VERSION 5.7 ;
  NOWIREEXTENSIONATPIN ON ;
  DIVIDERCHAR "/" ;
  BUSBITCHARS "[]" ;
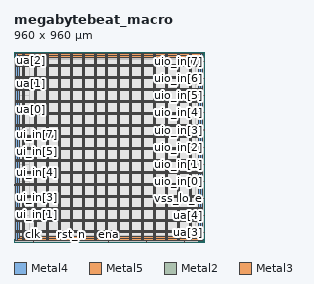
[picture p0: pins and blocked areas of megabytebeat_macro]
MACRO megabytebeat_macro
  CLASS BLOCK ;
  FOREIGN megabytebeat_macro ;
  ORIGIN 0.000 0.000 ;
  SIZE 960.000 BY 960.000 ;
  PIN VDD_BB
    DIRECTION INOUT ;
    USE POWER ;
    PORT
      LAYER Metal4 ;
        RECT 18.240 19.360 26.240 941.040 ;
    END
    PORT
      LAYER Metal4 ;
        RECT 933.600 19.360 941.600 941.040 ;
    END
    PORT
      LAYER Metal5 ;
        RECT 18.240 19.360 941.600 27.360 ;
    END
    PORT
      LAYER Metal5 ;
        RECT 18.240 933.040 941.600 941.040 ;
    END
    PORT
      LAYER Metal4 ;
        RECT 44.560 9.360 48.560 951.040 ;
    END
    PORT
      LAYER Metal4 ;
        RECT 104.560 9.360 108.560 951.040 ;
    END
    PORT
      LAYER Metal4 ;
        RECT 164.560 9.360 168.560 951.040 ;
    END
    PORT
      LAYER Metal4 ;
        RECT 224.560 9.360 228.560 951.040 ;
    END
    PORT
      LAYER Metal4 ;
        RECT 284.560 9.360 288.560 951.040 ;
    END
    PORT
      LAYER Metal4 ;
        RECT 344.560 9.360 348.560 951.040 ;
    END
    PORT
      LAYER Metal4 ;
        RECT 404.560 9.360 408.560 951.040 ;
    END
    PORT
      LAYER Metal4 ;
        RECT 464.560 9.360 468.560 951.040 ;
    END
    PORT
      LAYER Metal4 ;
        RECT 524.560 9.360 528.560 951.040 ;
    END
    PORT
      LAYER Metal4 ;
        RECT 584.560 9.360 588.560 951.040 ;
    END
    PORT
      LAYER Metal4 ;
        RECT 644.560 9.360 648.560 951.040 ;
    END
    PORT
      LAYER Metal4 ;
        RECT 704.560 9.360 708.560 951.040 ;
    END
    PORT
      LAYER Metal4 ;
        RECT 764.560 9.360 768.560 951.040 ;
    END
    PORT
      LAYER Metal4 ;
        RECT 824.560 9.360 828.560 951.040 ;
    END
    PORT
      LAYER Metal4 ;
        RECT 884.560 9.360 888.560 951.040 ;
    END
    PORT
      LAYER Metal5 ;
        RECT 8.240 46.010 951.600 50.010 ;
    END
    PORT
      LAYER Metal5 ;
        RECT 8.240 106.010 951.600 110.010 ;
    END
    PORT
      LAYER Metal5 ;
        RECT 8.240 166.010 951.600 170.010 ;
    END
    PORT
      LAYER Metal5 ;
        RECT 8.240 226.010 951.600 230.010 ;
    END
    PORT
      LAYER Metal5 ;
        RECT 8.240 286.010 951.600 290.010 ;
    END
    PORT
      LAYER Metal5 ;
        RECT 8.240 346.010 951.600 350.010 ;
    END
    PORT
      LAYER Metal5 ;
        RECT 8.240 406.010 951.600 410.010 ;
    END
    PORT
      LAYER Metal5 ;
        RECT 8.240 466.010 951.600 470.010 ;
    END
    PORT
      LAYER Metal5 ;
        RECT 8.240 526.010 951.600 530.010 ;
    END
    PORT
      LAYER Metal5 ;
        RECT 8.240 586.010 951.600 590.010 ;
    END
    PORT
      LAYER Metal5 ;
        RECT 8.240 646.010 951.600 650.010 ;
    END
    PORT
      LAYER Metal5 ;
        RECT 8.240 706.010 951.600 710.010 ;
    END
    PORT
      LAYER Metal5 ;
        RECT 8.240 766.010 951.600 770.010 ;
    END
    PORT
      LAYER Metal5 ;
        RECT 8.240 826.010 951.600 830.010 ;
    END
    PORT
      LAYER Metal5 ;
        RECT 8.240 886.010 951.600 890.010 ;
    END
  END VDD_BB
  PIN VSS
    DIRECTION INOUT ;
    USE GROUND ;
    PORT
      LAYER Metal4 ;
        RECT 8.240 9.360 16.240 951.040 ;
    END
    PORT
      LAYER Metal4 ;
        RECT 943.600 9.360 951.600 951.040 ;
    END
    PORT
      LAYER Metal5 ;
        RECT 8.240 9.360 951.600 17.360 ;
    END
    PORT
      LAYER Metal5 ;
        RECT 8.240 943.040 951.600 951.040 ;
    END
    PORT
      LAYER Metal4 ;
        RECT 50.560 9.360 54.560 951.040 ;
    END
    PORT
      LAYER Metal4 ;
        RECT 110.560 9.360 114.560 951.040 ;
    END
    PORT
      LAYER Metal4 ;
        RECT 170.560 9.360 174.560 951.040 ;
    END
    PORT
      LAYER Metal4 ;
        RECT 230.560 9.360 234.560 951.040 ;
    END
    PORT
      LAYER Metal4 ;
        RECT 290.560 9.360 294.560 951.040 ;
    END
    PORT
      LAYER Metal4 ;
        RECT 350.560 9.360 354.560 951.040 ;
    END
    PORT
      LAYER Metal4 ;
        RECT 410.560 9.360 414.560 951.040 ;
    END
    PORT
      LAYER Metal4 ;
        RECT 470.560 9.360 474.560 951.040 ;
    END
    PORT
      LAYER Metal4 ;
        RECT 530.560 9.360 534.560 951.040 ;
    END
    PORT
      LAYER Metal4 ;
        RECT 590.560 9.360 594.560 951.040 ;
    END
    PORT
      LAYER Metal4 ;
        RECT 650.560 9.360 654.560 951.040 ;
    END
    PORT
      LAYER Metal4 ;
        RECT 710.560 9.360 714.560 951.040 ;
    END
    PORT
      LAYER Metal4 ;
        RECT 770.560 9.360 774.560 951.040 ;
    END
    PORT
      LAYER Metal4 ;
        RECT 830.560 9.360 834.560 951.040 ;
    END
    PORT
      LAYER Metal4 ;
        RECT 890.560 9.360 894.560 951.040 ;
    END
    PORT
      LAYER Metal5 ;
        RECT 8.240 52.010 951.600 56.010 ;
    END
    PORT
      LAYER Metal5 ;
        RECT 8.240 112.010 951.600 116.010 ;
    END
    PORT
      LAYER Metal5 ;
        RECT 8.240 172.010 951.600 176.010 ;
    END
    PORT
      LAYER Metal5 ;
        RECT 8.240 232.010 951.600 236.010 ;
    END
    PORT
      LAYER Metal5 ;
        RECT 8.240 292.010 951.600 296.010 ;
    END
    PORT
      LAYER Metal5 ;
        RECT 8.240 352.010 951.600 356.010 ;
    END
    PORT
      LAYER Metal5 ;
        RECT 8.240 412.010 951.600 416.010 ;
    END
    PORT
      LAYER Metal5 ;
        RECT 8.240 472.010 951.600 476.010 ;
    END
    PORT
      LAYER Metal5 ;
        RECT 8.240 532.010 951.600 536.010 ;
    END
    PORT
      LAYER Metal5 ;
        RECT 8.240 592.010 951.600 596.010 ;
    END
    PORT
      LAYER Metal5 ;
        RECT 8.240 652.010 951.600 656.010 ;
    END
    PORT
      LAYER Metal5 ;
        RECT 8.240 712.010 951.600 716.010 ;
    END
    PORT
      LAYER Metal5 ;
        RECT 8.240 772.010 951.600 776.010 ;
    END
    PORT
      LAYER Metal5 ;
        RECT 8.240 832.010 951.600 836.010 ;
    END
    PORT
      LAYER Metal5 ;
        RECT 8.240 892.010 951.600 896.010 ;
    END
  END VSS
  PIN clk
    DIRECTION INPUT ;
    USE SIGNAL ;
    ANTENNAGATEAREA 5.464000 ;
    PORT
      LAYER Metal2 ;
        RECT 96.320 0.000 96.880 0.560 ;
    END
  END clk
  PIN ena
    DIRECTION INPUT ;
    USE SIGNAL ;
    ANTENNAGATEAREA 0.498500 ;
    PORT
      LAYER Metal2 ;
        RECT 479.360 0.000 479.920 0.560 ;
    END
  END ena
  PIN rst_n
    DIRECTION INPUT ;
    USE SIGNAL ;
    ANTENNAGATEAREA 0.498500 ;
    PORT
      LAYER Metal2 ;
        RECT 287.840 0.000 288.400 0.560 ;
    END
  END rst_n
  PIN ua[0]
    DIRECTION INOUT ;
    USE SIGNAL ;
    PORT
      LAYER Metal3 ;
        RECT 0.000 670.880 0.560 671.440 ;
    END
  END ua[0]
  PIN ua[1]
    DIRECTION INOUT ;
    USE SIGNAL ;
    PORT
      LAYER Metal3 ;
        RECT 0.000 798.560 0.560 799.120 ;
    END
  END ua[1]
  PIN ua[2]
    DIRECTION INOUT ;
    USE SIGNAL ;
    PORT
      LAYER Metal3 ;
        RECT 0.000 926.240 0.560 926.800 ;
    END
  END ua[2]
  PIN ua[3]
    DIRECTION INOUT ;
    USE SIGNAL ;
    PORT
      LAYER Metal3 ;
        RECT 959.440 48.160 960.000 48.720 ;
    END
  END ua[3]
  PIN ua[4]
    DIRECTION INOUT ;
    USE SIGNAL ;
    PORT
      LAYER Metal3 ;
        RECT 959.440 134.400 960.000 134.960 ;
    END
  END ua[4]
  PIN ui_in[0]
    DIRECTION INPUT ;
    USE SIGNAL ;
    ANTENNAGATEAREA 0.498500 ;
    PORT
      LAYER Metal3 ;
        RECT 0.000 32.480 0.560 33.040 ;
    END
  END ui_in[0]
  PIN ui_in[1]
    DIRECTION INPUT ;
    USE SIGNAL ;
    ANTENNAGATEAREA 0.498500 ;
    PORT
      LAYER Metal3 ;
        RECT 0.000 96.320 0.560 96.880 ;
    END
  END ui_in[1]
  PIN ui_in[2]
    DIRECTION INPUT ;
    USE SIGNAL ;
    ANTENNAGATEAREA 0.498500 ;
    PORT
      LAYER Metal3 ;
        RECT 0.000 160.160 0.560 160.720 ;
    END
  END ui_in[2]
  PIN ui_in[3]
    DIRECTION INPUT ;
    USE SIGNAL ;
    ANTENNAGATEAREA 0.498500 ;
    PORT
      LAYER Metal3 ;
        RECT 0.000 224.000 0.560 224.560 ;
    END
  END ui_in[3]
  PIN ui_in[4]
    DIRECTION INPUT ;
    USE SIGNAL ;
    ANTENNAGATEAREA 0.498500 ;
    PORT
      LAYER Metal3 ;
        RECT 0.000 351.680 0.560 352.240 ;
    END
  END ui_in[4]
  PIN ui_in[5]
    DIRECTION INPUT ;
    USE SIGNAL ;
    ANTENNAGATEAREA 1.102000 ;
    PORT
      LAYER Metal3 ;
        RECT 0.000 415.520 0.560 416.080 ;
    END
  END ui_in[5]
  PIN ui_in[6]
    DIRECTION INPUT ;
    USE SIGNAL ;
    ANTENNAGATEAREA 1.102000 ;
    PORT
      LAYER Metal3 ;
        RECT 0.000 479.360 0.560 479.920 ;
    END
  END ui_in[6]
  PIN ui_in[7]
    DIRECTION INPUT ;
    USE SIGNAL ;
    ANTENNAGATEAREA 1.102000 ;
    PORT
      LAYER Metal3 ;
        RECT 0.000 543.200 0.560 543.760 ;
    END
  END ui_in[7]
  PIN uio_in[0]
    DIRECTION INPUT ;
    USE SIGNAL ;
    ANTENNAGATEAREA 0.498500 ;
    PORT
      LAYER Metal3 ;
        RECT 959.440 306.880 960.000 307.440 ;
    END
  END uio_in[0]
  PIN uio_in[1]
    DIRECTION INPUT ;
    USE SIGNAL ;
    ANTENNAGATEAREA 0.498500 ;
    PORT
      LAYER Metal3 ;
        RECT 959.440 393.120 960.000 393.680 ;
    END
  END uio_in[1]
  PIN uio_in[2]
    DIRECTION INPUT ;
    USE SIGNAL ;
    ANTENNAGATEAREA 0.498500 ;
    PORT
      LAYER Metal3 ;
        RECT 959.440 479.360 960.000 479.920 ;
    END
  END uio_in[2]
  PIN uio_in[3]
    DIRECTION INPUT ;
    USE SIGNAL ;
    ANTENNAGATEAREA 0.498500 ;
    PORT
      LAYER Metal3 ;
        RECT 959.440 565.600 960.000 566.160 ;
    END
  END uio_in[3]
  PIN uio_in[4]
    DIRECTION INPUT ;
    USE SIGNAL ;
    ANTENNAGATEAREA 0.498500 ;
    PORT
      LAYER Metal3 ;
        RECT 959.440 651.840 960.000 652.400 ;
    END
  END uio_in[4]
  PIN uio_in[5]
    DIRECTION INPUT ;
    USE SIGNAL ;
    ANTENNAGATEAREA 1.102000 ;
    PORT
      LAYER Metal3 ;
        RECT 959.440 738.080 960.000 738.640 ;
    END
  END uio_in[5]
  PIN uio_in[6]
    DIRECTION INPUT ;
    USE SIGNAL ;
    ANTENNAGATEAREA 1.102000 ;
    PORT
      LAYER Metal3 ;
        RECT 959.440 824.320 960.000 824.880 ;
    END
  END uio_in[6]
  PIN uio_in[7]
    DIRECTION INPUT ;
    USE SIGNAL ;
    ANTENNAGATEAREA 1.102000 ;
    PORT
      LAYER Metal3 ;
        RECT 959.440 910.560 960.000 911.120 ;
    END
  END uio_in[7]
  PIN vdd_bb_hi_s
    DIRECTION OUTPUT ;
    USE SIGNAL ;
    ANTENNADIFFAREA 4.731200 ;
    PORT
      LAYER Metal2 ;
        RECT 670.880 0.000 671.440 0.560 ;
    END
  END vdd_bb_hi_s
  PIN vss_lo_e
    DIRECTION OUTPUT ;
    USE SIGNAL ;
    ANTENNADIFFAREA 4.731200 ;
    PORT
      LAYER Metal3 ;
        RECT 959.440 220.640 960.000 221.200 ;
    END
  END vss_lo_e
  PIN vss_lo_s
    DIRECTION OUTPUT ;
    USE SIGNAL ;
    ANTENNADIFFAREA 4.731200 ;
    PORT
      LAYER Metal2 ;
        RECT 862.400 0.000 862.960 0.560 ;
    END
  END vss_lo_s
  PIN vss_lo_w
    DIRECTION OUTPUT ;
    USE SIGNAL ;
    ANTENNADIFFAREA 4.731200 ;
    PORT
      LAYER Metal3 ;
        RECT 0.000 287.840 0.560 288.400 ;
    END
  END vss_lo_w
  OBS
      LAYER Nwell ;
        RECT 29.810 30.930 930.030 929.470 ;
      LAYER Metal1 ;
        RECT 30.240 31.060 929.600 929.340 ;
      LAYER Metal2 ;
        RECT 7.980 0.860 927.780 929.230 ;
        RECT 7.980 0.560 96.020 0.860 ;
        RECT 97.180 0.560 287.540 0.860 ;
        RECT 288.700 0.560 479.060 0.860 ;
        RECT 480.220 0.560 670.580 0.860 ;
        RECT 671.740 0.560 862.100 0.860 ;
        RECT 863.260 0.560 927.780 0.860 ;
      LAYER Metal3 ;
        RECT 0.560 927.100 959.440 929.180 ;
        RECT 0.860 925.940 959.440 927.100 ;
        RECT 0.560 911.420 959.440 925.940 ;
        RECT 0.560 910.260 959.140 911.420 ;
        RECT 0.560 825.180 959.440 910.260 ;
        RECT 0.560 824.020 959.140 825.180 ;
        RECT 0.560 799.420 959.440 824.020 ;
        RECT 0.860 798.260 959.440 799.420 ;
        RECT 0.560 738.940 959.440 798.260 ;
        RECT 0.560 737.780 959.140 738.940 ;
        RECT 0.560 671.740 959.440 737.780 ;
        RECT 0.860 670.580 959.440 671.740 ;
        RECT 0.560 652.700 959.440 670.580 ;
        RECT 0.560 651.540 959.140 652.700 ;
        RECT 0.560 566.460 959.440 651.540 ;
        RECT 0.560 565.300 959.140 566.460 ;
        RECT 0.560 544.060 959.440 565.300 ;
        RECT 0.860 542.900 959.440 544.060 ;
        RECT 0.560 480.220 959.440 542.900 ;
        RECT 0.860 479.060 959.140 480.220 ;
        RECT 0.560 416.380 959.440 479.060 ;
        RECT 0.860 415.220 959.440 416.380 ;
        RECT 0.560 393.980 959.440 415.220 ;
        RECT 0.560 392.820 959.140 393.980 ;
        RECT 0.560 352.540 959.440 392.820 ;
        RECT 0.860 351.380 959.440 352.540 ;
        RECT 0.560 307.740 959.440 351.380 ;
        RECT 0.560 306.580 959.140 307.740 ;
        RECT 0.560 288.700 959.440 306.580 ;
        RECT 0.860 287.540 959.440 288.700 ;
        RECT 0.560 224.860 959.440 287.540 ;
        RECT 0.860 223.700 959.440 224.860 ;
        RECT 0.560 221.500 959.440 223.700 ;
        RECT 0.560 220.340 959.140 221.500 ;
        RECT 0.560 161.020 959.440 220.340 ;
        RECT 0.860 159.860 959.440 161.020 ;
        RECT 0.560 135.260 959.440 159.860 ;
        RECT 0.560 134.100 959.140 135.260 ;
        RECT 0.560 97.180 959.440 134.100 ;
        RECT 0.860 96.020 959.440 97.180 ;
        RECT 0.560 49.020 959.440 96.020 ;
        RECT 0.560 47.860 959.140 49.020 ;
        RECT 0.560 33.340 959.440 47.860 ;
        RECT 0.860 32.180 959.440 33.340 ;
        RECT 0.560 16.380 959.440 32.180 ;
      LAYER Metal4 ;
        RECT 76.300 52.010 104.260 922.790 ;
        RECT 108.860 52.010 110.260 922.790 ;
        RECT 114.860 52.010 164.260 922.790 ;
        RECT 168.860 52.010 170.260 922.790 ;
        RECT 174.860 52.010 224.260 922.790 ;
        RECT 228.860 52.010 230.260 922.790 ;
        RECT 234.860 52.010 284.260 922.790 ;
        RECT 288.860 52.010 290.260 922.790 ;
        RECT 294.860 52.010 344.260 922.790 ;
        RECT 348.860 52.010 350.260 922.790 ;
        RECT 354.860 52.010 404.260 922.790 ;
        RECT 408.860 52.010 410.260 922.790 ;
        RECT 414.860 52.010 464.260 922.790 ;
        RECT 468.860 52.010 470.260 922.790 ;
        RECT 474.860 52.010 524.260 922.790 ;
        RECT 528.860 52.010 530.260 922.790 ;
        RECT 534.860 52.010 584.260 922.790 ;
        RECT 588.860 52.010 590.260 922.790 ;
        RECT 594.860 52.010 644.260 922.790 ;
        RECT 648.860 52.010 650.260 922.790 ;
        RECT 654.860 52.010 704.260 922.790 ;
        RECT 708.860 52.010 710.260 922.790 ;
        RECT 714.860 52.010 764.260 922.790 ;
        RECT 768.860 52.010 770.260 922.790 ;
        RECT 774.860 52.010 824.260 922.790 ;
        RECT 828.860 52.010 830.260 922.790 ;
        RECT 834.860 52.010 884.260 922.790 ;
        RECT 888.860 52.010 890.260 922.790 ;
        RECT 894.860 52.010 917.880 922.790 ;
  END
END megabytebeat_macro
END LIBRARY

